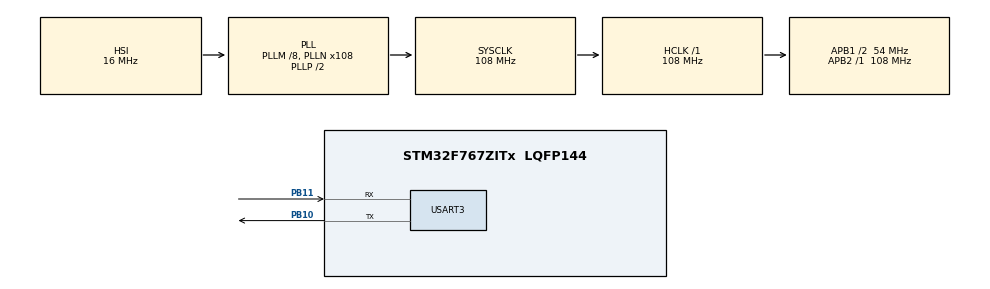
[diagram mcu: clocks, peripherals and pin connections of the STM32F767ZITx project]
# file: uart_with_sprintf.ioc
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Mcu.Family=STM32F7
Mcu.Name=STM32F767ZITx
Mcu.Package=LQFP144
NVIC.PriorityGroup=NVIC_PRIORITYGROUP_4
PB10.Mode=Asynchronous
PB10.Signal=USART3_TX
PB11.Mode=Asynchronous
PB11.Signal=USART3_RX
PH0/OSC_IN.Mode=HSE-External-Oscillator
PH0/OSC_IN.Signal=RCC_OSC_IN
PH1/OSC_OUT.Mode=HSE-External-Oscillator
PH1/OSC_OUT.Signal=RCC_OSC_OUT
ProjectManager.HeapSize=0x200
ProjectManager.StackSize=0x400
ProjectManager.TargetToolchain=STM32CubeIDE
RCC.48MHZClocksFreq_Value=24000000
RCC.AHBFreq_Value=108000000
RCC.APB1CLKDivider=RCC_HCLK_DIV2
RCC.APB1Freq_Value=54000000
RCC.APB1TimFreq_Value=108000000
RCC.APB2Freq_Value=108000000
RCC.APB2TimFreq_Value=108000000
RCC.CortexFreq_Value=108000000
RCC.HCLKFreq_Value=108000000
RCC.HSE_VALUE=8000000
RCC.HSI_VALUE=16000000
RCC.LSE_VALUE=32768
RCC.PLLM=8
RCC.PLLMUL=RCC_PLL_MUL9
RCC.PLLN=108
RCC.PRESCALERUSB=RCC_USBCLKSOURCE_PLL_DIV1_5
RCC.SYSCLKFreq_VALUE=108000000
RCC.SYSCLKSource=RCC_SYSCLKSOURCE_PLLCLK
RCC.SYSCLKSourceVirtual=RCC_SYSCLKSOURCE_PLLCLK
RCC.USBFreq_Value=108000000
RCC.VCOOutputFreq_Value=216000000
USART3.VirtualMode-Asynchronous=VM_ASYNC
board=NUCLEO-F767ZI

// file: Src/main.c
/* USER CODE BEGIN Header */
/**
  ******************************************************************************
  * @file           : main.c
  * @brief          : Main program body
  ******************************************************************************
  * @attention
  *
  * Copyright (c) 2025 STMicroelectronics.
  * All rights reserved.
  *
  * This software is licensed under terms that can be found in the LICENSE file
  * in the root directory of this software component.
  * If no LICENSE file comes with this software, it is provided AS-IS.
  *
  ******************************************************************************
  */
/* USER CODE END Header */
#include "main.h"

/* USER CODE BEGIN Includes */
#include <string.h>
/* USER CODE END Includes */

UART_HandleTypeDef huart3;

void SystemClock_Config(void);
static void MX_GPIO_Init(void);
static void MX_USART3_UART_Init(void);

int main(void)
{

  /* MCU Configuration--------------------------------------------------------*/

  /* Reset of all peripherals, Initializes the Flash interface and the Systick. */
  HAL_Init();

  /* Configure the system clock */
  SystemClock_Config();

  /* Initialize all configured peripherals */
  MX_GPIO_Init();
  MX_USART3_UART_Init();

  /* USER CODE BEGIN 2 */
  // Initialize an empty buffer with 100 free spots to fill later
  char transmit_buffer[100];
  uint8_t timeout = 100;
  int tall = 50;
  /* USER CODE END 2 */

  /* Infinite loop */
  while (1)
  {

    /* USER CODE BEGIN 3 */
    // Prepare/Update the string we want to transmit through UART
    sprintf(transmit_buffer, "Sensorvalue : %d \n", tall);
    HAL_UART_Transmit(&huart3, transmit_buffer, strlen(transmit_buffer), timeout);
    HAL_Delay(1000);
    tall++;
  }
  /* USER CODE END 3 */
}

void SystemClock_Config(void)
{
  RCC_OscInitTypeDef RCC_OscInitStruct = {0};
  RCC_ClkInitTypeDef RCC_ClkInitStruct = {0};

  /** Configure the main internal regulator output voltage
  */
  __HAL_RCC_PWR_CLK_ENABLE();
  __HAL_PWR_VOLTAGESCALING_CONFIG(PWR_REGULATOR_VOLTAGE_SCALE3);

  /** Initializes the RCC Oscillators according to the specified parameters
  * in the RCC_OscInitTypeDef structure.
  */
  RCC_OscInitStruct.OscillatorType = RCC_OSCILLATORTYPE_HSI;
  RCC_OscInitStruct.HSIState = RCC_HSI_ON;
  RCC_OscInitStruct.HSICalibrationValue = RCC_HSICALIBRATION_DEFAULT;
  RCC_OscInitStruct.PLL.PLLState = RCC_PLL_ON;
  RCC_OscInitStruct.PLL.PLLSource = RCC_PLLSOURCE_HSI;
  RCC_OscInitStruct.PLL.PLLM = 8;
  RCC_OscInitStruct.PLL.PLLN = 108;
  RCC_OscInitStruct.PLL.PLLP = RCC_PLLP_DIV2;
  RCC_OscInitStruct.PLL.PLLQ = 2;
  RCC_OscInitStruct.PLL.PLLR = 2;
  if (HAL_RCC_OscConfig(&RCC_OscInitStruct) != HAL_OK)
  {
    Error_Handler();
  }

  /** Activate the Over-Drive mode
  */
  if (HAL_PWREx_EnableOverDrive() != HAL_OK)
  {
    Error_Handler();
  }

  /** Initializes the CPU, AHB and APB buses clocks
  */
  RCC_ClkInitStruct.ClockType = RCC_CLOCKTYPE_HCLK|RCC_CLOCKTYPE_SYSCLK
                              |RCC_CLOCKTYPE_PCLK1|RCC_CLOCKTYPE_PCLK2;
  RCC_ClkInitStruct.SYSCLKSource = RCC_SYSCLKSOURCE_PLLCLK;
  RCC_ClkInitStruct.AHBCLKDivider = RCC_SYSCLK_DIV1;
  RCC_ClkInitStruct.APB1CLKDivider = RCC_HCLK_DIV2;
  RCC_ClkInitStruct.APB2CLKDivider = RCC_HCLK_DIV1;

  if (HAL_RCC_ClockConfig(&RCC_ClkInitStruct, FLASH_LATENCY_3) != HAL_OK)
  {
    Error_Handler();
  }
}

static void MX_USART3_UART_Init(void)
{

  huart3.Instance = USART3;
  huart3.Init.BaudRate = 115200;
  huart3.Init.WordLength = UART_WORDLENGTH_8B;
  huart3.Init.StopBits = UART_STOPBITS_1;
  huart3.Init.Parity = UART_PARITY_NONE;
  huart3.Init.Mode = UART_MODE_TX_RX;
  huart3.Init.HwFlowCtl = UART_HWCONTROL_NONE;
  huart3.Init.OverSampling = UART_OVERSAMPLING_16;
  huart3.Init.OneBitSampling = UART_ONE_BIT_SAMPLE_DISABLE;
  huart3.AdvancedInit.AdvFeatureInit = UART_ADVFEATURE_NO_INIT;
  if (HAL_UART_Init(&huart3) != HAL_OK)
  {
    Error_Handler();
  }

}

static void MX_GPIO_Init(void)
{
  GPIO_InitTypeDef GPIO_InitStruct = {0};

  /* GPIO Ports Clock Enable */
  __HAL_RCC_GPIOH_CLK_ENABLE();
  __HAL_RCC_GPIOB_CLK_ENABLE();
  __HAL_RCC_GPIOD_CLK_ENABLE();

  /*Configure GPIO pin Output Level */
  HAL_GPIO_WritePin(GPIOB, LD1_Pin|LD3_Pin|LD2_Pin, GPIO_PIN_RESET);

  /*Configure GPIO pins : LD1_Pin LD3_Pin LD2_Pin */
  GPIO_InitStruct.Pin = LD1_Pin|LD3_Pin|LD2_Pin;
  GPIO_InitStruct.Mode = GPIO_MODE_OUTPUT_PP;
  GPIO_InitStruct.Pull = GPIO_NOPULL;
  GPIO_InitStruct.Speed = GPIO_SPEED_FREQ_LOW;
  HAL_GPIO_Init(GPIOB, &GPIO_InitStruct);

}

void Error_Handler(void)
{
  __disable_irq();
  while (1)
  {
  }
}
